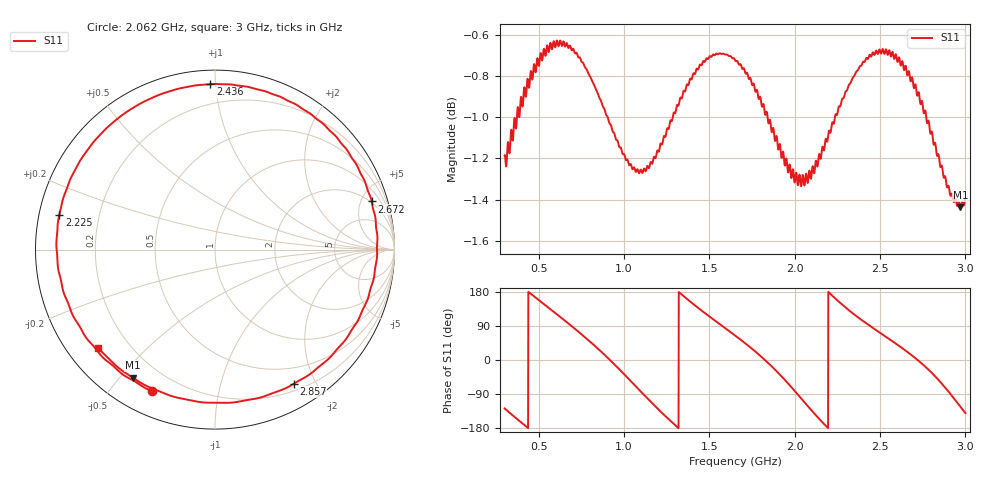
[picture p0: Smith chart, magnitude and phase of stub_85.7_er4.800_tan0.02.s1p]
! Chirptenna · simulación 3D de un stub abierto
# HZ S RI R 50
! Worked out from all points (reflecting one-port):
!   2001 points, 300 MHz to 3 GHz, reference 50 ohm
!   lowest |S11| = -1.4 dB at 2.97 GHz (marker M1), VSWR 12.12, Z = 5.34 - j27 ohm
!   phase of S11 starts at -128 deg and turns -1092 deg over the sweep
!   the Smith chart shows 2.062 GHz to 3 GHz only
!   S11 on the Smith chart (normalised r, x): 2.062 GHz: 0.11, -0.65; 2.225 GHz: 0.06, +0.11; 2.436 GHz: 0.08, +0.97; 2.672 GHz: 1.88, +6.09; 2.857 GHz: 0.28, -1.71; 3 GHz: 0.09, -0.36
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3e8  -0.5349 -0.6892
4.6335e8  -0.8999 0.1375
6.375e8  -0.3089 0.8749
7.8465e8  0.5278 0.7471
8.859e8  0.8701 0.2098
9.75e8  0.7891 -0.3812
1.056e9  0.3868 -0.7754
1.13025e9  -0.125 -0.8564
1.22745e9  -0.6933 -0.5412
1.3125e9  -0.8965 -0.0414
1.49205e9  -0.4261 0.8163
1.65e9  0.3918 0.8327
1.82955e9  0.8923 -0.0243
1.9038e9  0.7231 -0.4932
1.9875e9  0.2196 -0.837
2.06175e9  -0.3483 -0.7873
2.1468e9  -0.8038 -0.3389
2.2251e9  -0.8667 0.1946
2.325e9  -0.5652 0.711
2.4357e9  -0.0254 0.9221
2.5437e9  0.4855 0.785
2.6625e9  0.855 0.3197
2.67195e9  0.8731 0.2685
2.7705e9  0.8372 -0.3059
2.8569e9  0.4379 -0.7483
2.9136e9  -0.000934 -0.8529
2.9703e9  -0.4588 -0.7126
3e9  -0.6529 -0.5466
